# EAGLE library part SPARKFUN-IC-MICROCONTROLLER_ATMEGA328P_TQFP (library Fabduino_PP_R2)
Popular 328P in QFP Storefront component: ATmega328 - TQFP (COM-13448) Datasheet SparkFun Products SparkFun RedBoard - Programmed with Arduino (DEV-12757) Arduino Pro Mini 328 - 5V/16MHz (DEV-11113) Arduino Pro Mini 328 - 3.3V/8MHz (DEV-11114) SparkFun OpenLog (DEV-13712) SparkFun MicroView - OLED Arduino Module (DEV-12923) SparkFun Digital Sandbox (DEV-12651) SparkFun PicoBoard (WIG-11888) Arduino Fio (DEV-10116) LilyPad Arduino 328 Main Board (DEV-13342) SparkFun RedStick (DEV-13741) LilyPad MP3 (DEV-11013) LilyPad Arduino SimpleSnap (DEV-10941) SparkFun Stepoko (ROB-13899) SparkFun Geiger Counter (SEN-11345) SparkFun EL Sequencer (COM-12781) Arduino Pro 328 - 5V/16MHz (DEV-10915) CryptoCape (DEV-12773) SparkFun IR Thermometer Evaluation Board - MLX90614 (SEN-10740) SparkFun RedBot Mainboard (ROB-12097) Arduino Pro 328 - 3.3V/8MHz (DEV-10914) SparkFun Block for Intel® Edison - Arduino (DEV-13036) SparkFun Simon Says - Surface Mount Soldering Kit (KIT-10935) SparkFun 7-Segment Serial Display - Red (COM-11441) SparkFun 7-Segment Serial Display - White (COM-11629) SparkFun 7-Segment Serial Display - Yellow (COM-11443) SparkFun 7-Segment Serial Display - Kelly Green (COM-11440) SparkFun 7-Segment Serial Display - Blue (COM-11442) SparkFun OpenSegment Serial Display - 20mm (Blue) (COM-11647) SparkFun OpenSegment Serial Display - 20mm (Green) (COM-11646) SparkFun OpenSegment Serial Display - 20mm (White) (COM-11648) SparkFun OpenSegment Serial Display - 20mm (Red) (COM-11644)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

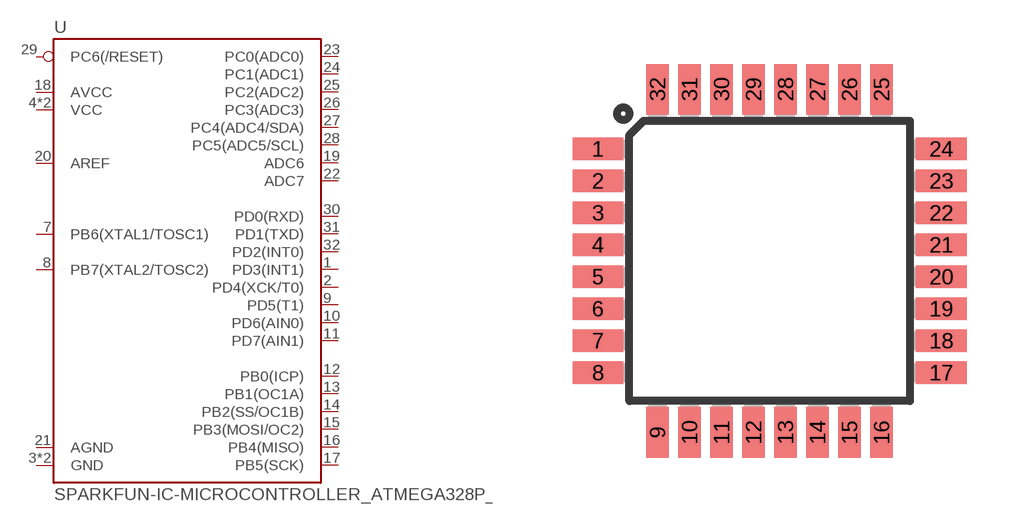
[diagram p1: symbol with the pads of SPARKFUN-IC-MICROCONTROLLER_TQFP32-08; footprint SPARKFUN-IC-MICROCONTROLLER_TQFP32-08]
Designator prefix U

## SPARKFUN-IC-MICROCONTROLLER_ATMEGA328P_TQFP (PROD_ID: IC-09069; VALUE: ATMEGA328P_TQFP)  [SPARKFUN-IC-MICROCONTROLLER_TQFP32-08]
1  PD3(INT1)
2  PD4(XCK/T0)
3  GND
4  VCC
5  GND
6  VCC
7  PB6(XTAL1/TOSC1)
8  PB7(XTAL2/TOSC2)
9  PD5(T1)
10  PD6(AIN0)
11  PD7(AIN1)
12  PB0(ICP)
13  PB1(OC1A)
14  PB2(SS/OC1B)
15  PB3(MOSI/OC2)
16  PB4(MISO)
17  PB5(SCK)
18  AVCC
19  ADC6
20  AREF
21  AGND
22  ADC7
23  PC0(ADC0)
24  PC1(ADC1)
25  PC2(ADC2)
26  PC3(ADC3)
27  PC4(ADC4/SDA)
28  PC5(ADC5/SCL)
29  PC6(/RESET)
30  PD0(RXD)
31  PD1(TXD)
32  PD2(INT0)

## Footprint SPARKFUN-IC-MICROCONTROLLER_TQFP32-08 (pad centres in mm)
Thin Plasic Quad Flat Package Grid 0.8 mm
smd 1.27 x 0.559: 1 -4.293,2.8; 2 -4.293,2; 3 -4.293,1.2; 4 -4.293,0.4; 5 -4.293,-0.4; 6 -4.293,-1.2; 7 -4.293,-2; 8 -4.293,-2.8; 17 4.293,-2.8; 18 4.293,-2; 19 4.293,-1.2; 20 4.293,-0.4; 21 4.293,0.4; 22 4.293,1.2; 23 4.293,2; 24 4.293,2.8
smd 0.559 x 1.27: 9 -2.8,-4.293; 10 -2,-4.293; 11 -1.2,-4.293; 12 -0.4,-4.293; 13 0.4,-4.293; 14 1.2,-4.293; 15 2,-4.293; 16 2.8,-4.293; 25 2.8,4.293; 26 2,4.293; 27 1.2,4.293; 28 0.4,4.293; 29 -0.4,4.293; 30 -1.2,4.293; 31 -2,4.293; 32 -2.8,4.293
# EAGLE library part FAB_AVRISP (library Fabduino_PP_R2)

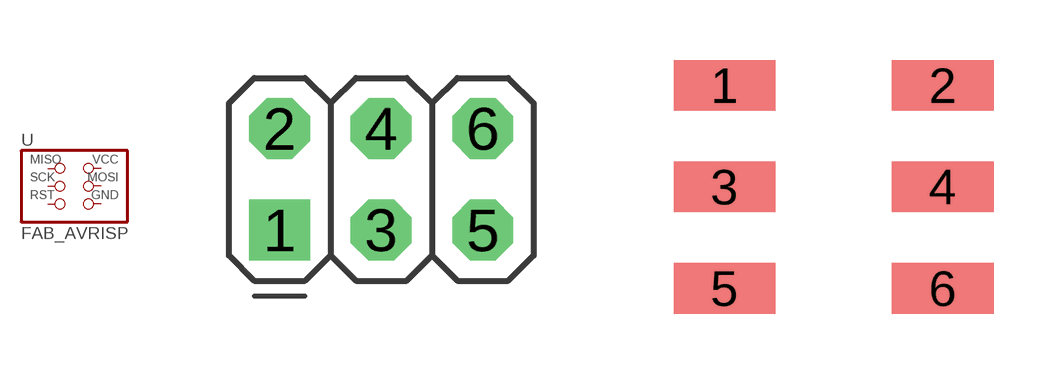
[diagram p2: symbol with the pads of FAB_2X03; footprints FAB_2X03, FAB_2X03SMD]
Designator prefix -

## FAB_AVRISP  [FAB_2X03]
1  MISO  pas
2  VCC  pas
3  SCK  pas
4  MOSI  pas
5  RST  pas
6  GND  pas

## FAB_AVRISPSMD  [FAB_2X03SMD]
Pads as for FAB_2X03

## Footprint FAB_2X03 (pad centres in mm)
PIN HEADER
drill 1.016 square: 1 -2.54,-1.27
drill 1.016 octagon: 2 -2.54,1.27; 3 0,-1.27; 4 0,1.27; 5 2.54,-1.27; 6 2.54,1.27

## Footprint FAB_2X03SMD (pad centres in mm)
smd 2.54 x 1.27: 1 -2.54,2.54; 2 2.92,2.54; 3 -2.54,0; 4 2.92,0; 5 -2.54,-2.54; 6 2.92,-2.54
